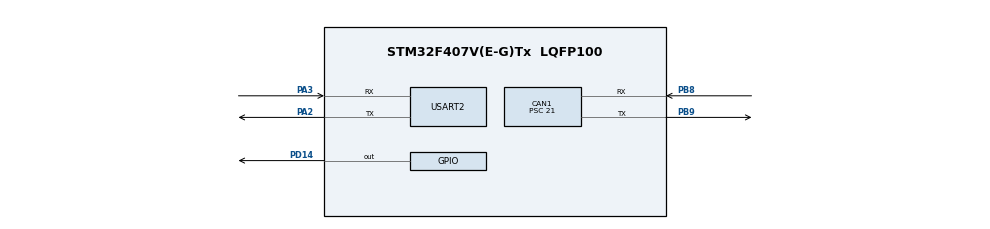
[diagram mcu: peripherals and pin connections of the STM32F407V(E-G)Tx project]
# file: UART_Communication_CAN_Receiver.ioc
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CAN1.BS1=CAN_BS1_2TQ
CAN1.CalculateBaudRate=74404
CAN1.CalculateTimeBit=13440
CAN1.CalculateTimeQuantum=3360.0
CAN1.Prescaler=21
FREERTOS.INCLUDE_vTaskDelayUntil=1
FREERTOS.Tasks01=defaultTask,-3,128,StartDefaultTask,Default,NULL,Dynamic,NULL,NULL
FREERTOS.configUSE_NEWLIB_REENTRANT=1
Mcu.Family=STM32F4
Mcu.Name=STM32F407V(E-G)Tx
Mcu.Package=LQFP100
NVIC.CAN1_RX0_IRQn=true\:5\:0\:false\:false\:true\:true\:true\:true\:true
NVIC.PriorityGroup=NVIC_PRIORITYGROUP_4
NVIC.TIM1_UP_TIM10_IRQn=true\:15\:0\:false\:false\:true\:false\:false\:true\:true
NVIC.TimeBase=TIM1_UP_TIM10_IRQn
NVIC.TimeBaseIP=TIM1
PA2.Mode=Asynchronous
PA2.Signal=USART2_TX
PA3.Mode=Asynchronous
PA3.Signal=USART2_RX
PB8.Mode=CAN_Activate
PB8.Signal=CAN1_RX
PB9.Mode=CAN_Activate
PB9.Signal=CAN1_TX
PD14.Signal=GPIO_Output
PH0-OSC_IN.Mode=HSE-External-Oscillator
PH0-OSC_IN.Signal=RCC_OSC_IN
PH1-OSC_OUT.Mode=HSE-External-Oscillator
PH1-OSC_OUT.Signal=RCC_OSC_OUT
ProjectManager.HeapSize=0x200
ProjectManager.StackSize=0x400
ProjectManager.TargetToolchain=STM32CubeIDE
RCC.48MHZClocksFreq_Value=14285714.285714285
RCC.AHBFreq_Value=25000000
RCC.APB1CLKDivider=RCC_HCLK_DIV4
RCC.APB1Freq_Value=6250000
RCC.APB1TimFreq_Value=12500000
RCC.APB2CLKDivider=RCC_HCLK_DIV2
RCC.APB2Freq_Value=12500000
RCC.APB2TimFreq_Value=25000000
RCC.CortexFreq_Value=25000000
RCC.HCLKFreq_Value=25000000
RCC.HSE_VALUE=8000000
RCC.HSI_VALUE=16000000
RCC.LSE_VALUE=32768
RCC.PLLM=8
RCC.PLLN=50
RCC.PLLP=RCC_PLLP_DIV4
RCC.PLLQ=7
RCC.SYSCLKFreq_VALUE=25000000
RCC.SYSCLKSource=RCC_SYSCLKSOURCE_PLLCLK
RCC.VCOOutputFreq_Value=100000000
USART2.VirtualMode=VM_ASYNC
VP_FREERTOS_VS_CMSIS_V1.Mode=CMSIS_V1
VP_SYS_VS_tim1.Mode=TIM1
board=STM32F407G-DISC1

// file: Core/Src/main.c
/* USER CODE BEGIN Header */
/**
 ******************************************************************************
 * @file           : main.c
 * @brief          : FreeRTOS-based CAN Receiver
 ******************************************************************************
 */
/* USER CODE END Header */
#include "main.h"
#include "cmsis_os.h"

/* USER CODE BEGIN Includes */
#include <stdio.h>
#include <string.h>
/* USER CODE END Includes */

/* USER CODE BEGIN PTD */
typedef struct {
	uint16_t ppm;
	uint32_t adcValue;
	uint16_t temperature;
	uint16_t humidity;
} CANMessage_t;

/* USER CODE END PTD */

CAN_HandleTypeDef hcan1;

UART_HandleTypeDef huart2;
QueueHandle_t xQueueCAN;

osThreadId defaultTaskHandle, CANTaskHandle;

void SystemClock_Config(void);
static void MX_GPIO_Init(void);
static void MX_CAN1_Init(void);
static void MX_USART2_UART_Init(void);
void StartDefaultTask(void const *argument);
void vCANTask(void *pvParam);
void Error_Handler(void);

/* USER CODE BEGIN 0 */
/* USER CODE BEGIN 0 */
/* UART Message Formatting */
void send_UART_message(CANMessage_t msg) {
	char uartMessage[120];
	snprintf(uartMessage, sizeof(uartMessage),
			"MQ-135 PPM: %d | ADC: %lu | Temp: %.2f°C | Humidity: %.2f%%\r\n",
			msg.ppm, msg.adcValue, msg.temperature / 100.0,
			msg.humidity / 100.0);

	HAL_UART_Transmit(&huart2, (uint8_t*) uartMessage, strlen(uartMessage),
	HAL_MAX_DELAY);
}

/* CAN Interrupt Callback */
void HAL_CAN_RxFifo0MsgPendingCallback(CAN_HandleTypeDef *hcan) {
	CAN_RxHeaderTypeDef RxHeader;
	uint8_t RxData[8];
	CANMessage_t msg;

	if (HAL_CAN_GetRxMessage(&hcan1, CAN_RX_FIFO0, &RxHeader, RxData)
			== HAL_OK) {
		if (RxHeader.StdId == 0x103 && RxHeader.DLC == 8) {
			/* Extract 8-byte CAN data */
			msg.ppm = (RxData[0] << 8) | RxData[1];
			msg.adcValue = (RxData[2] << 24) | (RxData[3] << 16)
					| (RxData[4] << 8) | RxData[5];
			msg.temperature = (RxData[6] << 8) | RxData[7];
			msg.humidity = 0;

			/* Send message to queue */
			BaseType_t xHigherPriorityTaskWoken = pdFALSE;
			if (uxQueueSpacesAvailable(xQueueCAN) > 0) {
				xQueueSendFromISR(xQueueCAN, &msg, &xHigherPriorityTaskWoken);
				portYIELD_FROM_ISR(xHigherPriorityTaskWoken);
			} else {
				/* Queue Overflow Handling */
				HAL_GPIO_TogglePin(GPIOD, GPIO_PIN_14); // Indicate queue overflow
				char errorMsg[] = "Queue Overflow! Data Lost.\r\n";
				HAL_UART_Transmit(&huart2, (uint8_t*) errorMsg,
						strlen(errorMsg), HAL_MAX_DELAY);
			}
		}
	}
}

/* CAN Reception Task */
void vCANTask(void *pvParam) {
	CANMessage_t receivedMsg;

	while (1) {
		if (xQueueReceive(xQueueCAN, &receivedMsg, portMAX_DELAY) == pdPASS) {
			/* Blink LED to indicate successful reception */
			HAL_GPIO_TogglePin(GPIOD, GPIO_PIN_14);
			vTaskDelay(pdMS_TO_TICKS(50));
			HAL_GPIO_TogglePin(GPIOD, GPIO_PIN_14);

			/* Send Data Over UART */
			send_UART_message(receivedMsg);
		}
	}
}
int main(void) {
	HAL_Init();
	SystemClock_Config();
	MX_GPIO_Init();
	MX_CAN1_Init();
	MX_USART2_UART_Init();

	/* Start CAN */
	if (HAL_CAN_Start(&hcan1) != HAL_OK) {
		Error_Handler();
	}
	HAL_CAN_ActivateNotification(&hcan1, CAN_IT_RX_FIFO0_MSG_PENDING);

	/* Create Queue */
	xQueueCAN = xQueueCreate(10, sizeof(CANMessage_t));
	if (xQueueCAN == NULL) {
		Error_Handler();
	}

	/* Create Task */
	xTaskCreate(vCANTask, "CANTask", configMINIMAL_STACK_SIZE + 256, NULL, 4,
			&CANTaskHandle);
	osKernelStart();

	while (1) {
	}
}

void SystemClock_Config(void) {
	RCC_OscInitTypeDef RCC_OscInitStruct = { 0 };
	RCC_ClkInitTypeDef RCC_ClkInitStruct = { 0 };

	/** Configure the main internal regulator output voltage
	 */
	__HAL_RCC_PWR_CLK_ENABLE();
	__HAL_PWR_VOLTAGESCALING_CONFIG(PWR_REGULATOR_VOLTAGE_SCALE1);

	/** Initializes the RCC Oscillators according to the specified parameters
	 * in the RCC_OscInitTypeDef structure.
	 */
	RCC_OscInitStruct.OscillatorType = RCC_OSCILLATORTYPE_HSI;
	RCC_OscInitStruct.HSIState = RCC_HSI_ON;
	RCC_OscInitStruct.HSICalibrationValue = RCC_HSICALIBRATION_DEFAULT;
	RCC_OscInitStruct.PLL.PLLState = RCC_PLL_ON;
	RCC_OscInitStruct.PLL.PLLSource = RCC_PLLSOURCE_HSI;
	RCC_OscInitStruct.PLL.PLLM = 8;
	RCC_OscInitStruct.PLL.PLLN = 336;
	RCC_OscInitStruct.PLL.PLLP = RCC_PLLP_DIV4;
	RCC_OscInitStruct.PLL.PLLQ = 7;
	if (HAL_RCC_OscConfig(&RCC_OscInitStruct) != HAL_OK) {
		Error_Handler();
	}

	/** Initializes the CPU, AHB and APB buses clocks
	 */
	RCC_ClkInitStruct.ClockType = RCC_CLOCKTYPE_HCLK | RCC_CLOCKTYPE_SYSCLK
			| RCC_CLOCKTYPE_PCLK1 | RCC_CLOCKTYPE_PCLK2;
	RCC_ClkInitStruct.SYSCLKSource = RCC_SYSCLKSOURCE_PLLCLK;
	RCC_ClkInitStruct.AHBCLKDivider = RCC_SYSCLK_DIV1;
	RCC_ClkInitStruct.APB1CLKDivider = RCC_HCLK_DIV4;
	RCC_ClkInitStruct.APB2CLKDivider = RCC_HCLK_DIV2;

	if (HAL_RCC_ClockConfig(&RCC_ClkInitStruct, FLASH_LATENCY_0) != HAL_OK) {
		Error_Handler();
	}
}

static void MX_CAN1_Init(void) {
	hcan1.Instance = CAN1;
	hcan1.Init.Prescaler = 21;
	hcan1.Init.Mode = CAN_MODE_NORMAL;
	hcan1.Init.SyncJumpWidth = CAN_SJW_1TQ;
	hcan1.Init.TimeSeg1 = CAN_BS1_2TQ;
	hcan1.Init.TimeSeg2 = CAN_BS2_1TQ;
	hcan1.Init.TimeTriggeredMode = DISABLE;
	hcan1.Init.AutoBusOff = DISABLE;
	hcan1.Init.AutoWakeUp = DISABLE;
	hcan1.Init.AutoRetransmission = DISABLE;
	hcan1.Init.ReceiveFifoLocked = DISABLE;
	hcan1.Init.TransmitFifoPriority = DISABLE;
	if (HAL_CAN_Init(&hcan1) != HAL_OK) {
		Error_Handler();
	}

	/* USER CODE BEGIN CAN1_Init 2 */
	CAN_FilterTypeDef canfilterconfig;
	canfilterconfig.FilterActivation = CAN_FILTER_ENABLE;
	canfilterconfig.FilterBank = 0;
	canfilterconfig.FilterFIFOAssignment = CAN_FILTER_FIFO0;
	canfilterconfig.FilterIdHigh = 0x123 << 5;
	canfilterconfig.FilterIdLow = 0;
	canfilterconfig.FilterMaskIdHigh = 0x103 << 5;
	canfilterconfig.FilterMaskIdLow = 0x0000;
	canfilterconfig.FilterMode = CAN_FILTERMODE_IDMASK;
	canfilterconfig.FilterScale = CAN_FILTERSCALE_32BIT;
	canfilterconfig.SlaveStartFilterBank = 14;

	if (HAL_CAN_ConfigFilter(&hcan1, &canfilterconfig) != HAL_OK) {
		Error_Handler();
	}

	if (HAL_CAN_Start(&hcan1) != HAL_OK) {
		Error_Handler();
	}
}
static void MX_USART2_UART_Init(void) {

	huart2.Instance = USART2;
	huart2.Init.BaudRate = 115200;
	huart2.Init.WordLength = UART_WORDLENGTH_8B;
	huart2.Init.StopBits = UART_STOPBITS_1;
	huart2.Init.Parity = UART_PARITY_NONE;
	huart2.Init.Mode = UART_MODE_TX_RX;
	huart2.Init.HwFlowCtl = UART_HWCONTROL_NONE;
	huart2.Init.OverSampling = UART_OVERSAMPLING_16;
	if (HAL_UART_Init(&huart2) != HAL_OK) {
		Error_Handler();
	}

}

static void MX_GPIO_Init(void) {
	GPIO_InitTypeDef GPIO_InitStruct = { 0 };
	__HAL_RCC_GPIOH_CLK_ENABLE();
	__HAL_RCC_GPIOA_CLK_ENABLE();
	__HAL_RCC_GPIOD_CLK_ENABLE();
	__HAL_RCC_GPIOB_CLK_ENABLE();
	HAL_GPIO_WritePin(GPIOD, GPIO_PIN_14, GPIO_PIN_RESET);
	GPIO_InitStruct.Pin = GPIO_PIN_14;
	GPIO_InitStruct.Mode = GPIO_MODE_OUTPUT_PP;
	GPIO_InitStruct.Pull = GPIO_NOPULL;
	GPIO_InitStruct.Speed = GPIO_SPEED_FREQ_LOW;
	HAL_GPIO_Init(GPIOD, &GPIO_InitStruct);
}

void StartDefaultTask(void const *argument) {
	for (;;) {
		osDelay(1);
	}
}

void HAL_TIM_PeriodElapsedCallback(TIM_HandleTypeDef *htim) {
	if (htim->Instance == TIM1) {
		HAL_IncTick();
	}
}

void Error_Handler(void) {
	/* USER CODE BEGIN Error_Handler_Debug */
	/* User can add his own implementation to report the HAL error return state */
	while (1) {
		HAL_GPIO_TogglePin(GPIOD, GPIO_PIN_14);
		HAL_Delay(500);
	}
	/* USER CODE END Error_Handler_Debug */
}
